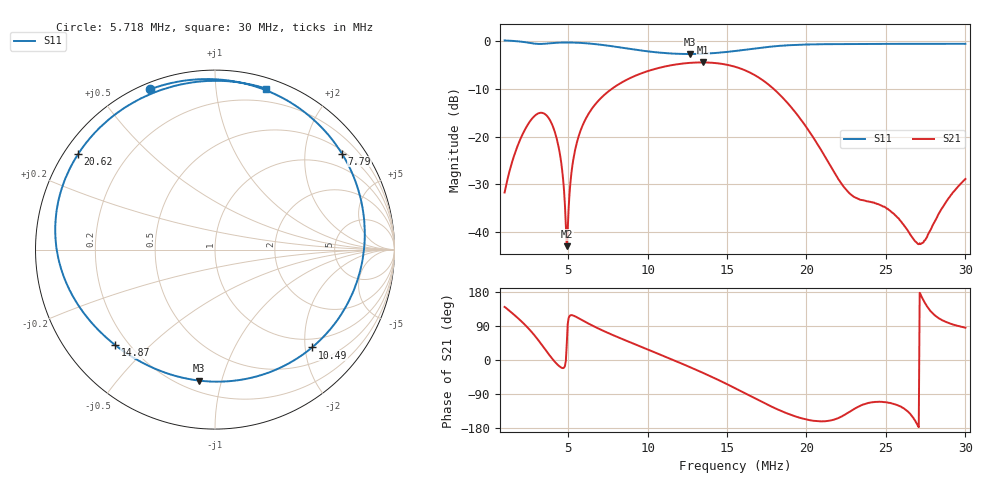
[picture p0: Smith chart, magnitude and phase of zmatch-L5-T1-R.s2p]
# HZ S RI R 50
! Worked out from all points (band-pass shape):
!   505 points, 1 MHz to 30 MHz, reference 50 ohm
!   highest |S21| = -4.44 dB at 13.49 MHz (marker M1); lowest = -43.0 dB at 4.913 MHz (marker M2)
!   |S21| within 3 dB of the highest: 9.087 MHz to 16.91 MHz (7.824 MHz wide, 60.2 % of centre)
!   lowest |S11| = -2.7 dB at 12.68 MHz (marker M3), VSWR 6.55, Z = 13.4 - j42.5 ohm
!   |S11| at or under -10 dB: nowhere
!   S12 and S22 are empty: the file has one direction only
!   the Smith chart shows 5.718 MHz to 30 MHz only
!   S11 on the Smith chart (normalised r, x): 5.718 MHz: 0.03, +0.67; 7.79 MHz: 0.57, +2.88; 10.49 MHz: 0.81, -2.15; 14.87 MHz: 0.15, -0.39; 20.62 MHz: 0.04, +0.31; 30 MHz: 0.09, +1.36
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1000000  -0.6046 0.8223  -0.0198 0.0166  0 0  0 0
1978180  0.3627 0.9257  -0.0242 0.0895  0 0  0 0
2668660  0.9555 0.0515  0.0375 0.1451  0 0  0 0
3128980  0.5365 -0.7697  0.108 0.138  0 0  0 0
3474220  -0.1409 -0.9305  0.1474 0.0939  0 0  0 0
4107160  -0.9074 -0.3177  0.1186 -0.00446  0 0  0 0
4912720  -0.8281 0.509  0.0052 0.00477  0 0  0 0
5718280  -0.3607 0.8934  -0.0349 0.1019  0 0  0 0
5833360  -0.2866 0.9173  -0.0342 0.1168  0 0  0 0
7789720  0.7069 0.5351  0.1293 0.2931  0 0  0 0
1.04941e7  0.5409 -0.5451  0.4852 0.1701  0 0  0 0
1.066672e7  0.4921 -0.5828  0.5022 0.1473  0 0  0 0
1.268062e7  -0.0887 -0.7297  0.5614 -0.1939  0 0  0 0
1.348618e7  -0.2845 -0.6831  0.4978 -0.3351  0 0  0 0
1.486714e7  -0.5553 -0.5326  0.2773 -0.5007  0 0  0 0
1.550008e7  -0.656 -0.4417  0.1473 -0.52  0 0  0 0
1.76866e7  -0.8765 -0.031  -0.1751 -0.2947  0 0  0 0
2.033344e7  -0.7903 0.4864  -0.0968 -0.0357  0 0  0 0
2.062114e7  -0.7639 0.5305  -0.0823 -0.028  0 0  0 0
2.51668e7  -0.2325 0.9101  -0.00667 -0.0157  0 0  0 0
2.723824e7  0.00568 0.9406  -0.00735 0.00165  0 0  0 0
3.000016e7  0.2832 0.8974  0.00308 0.0357  0 0  0 0
